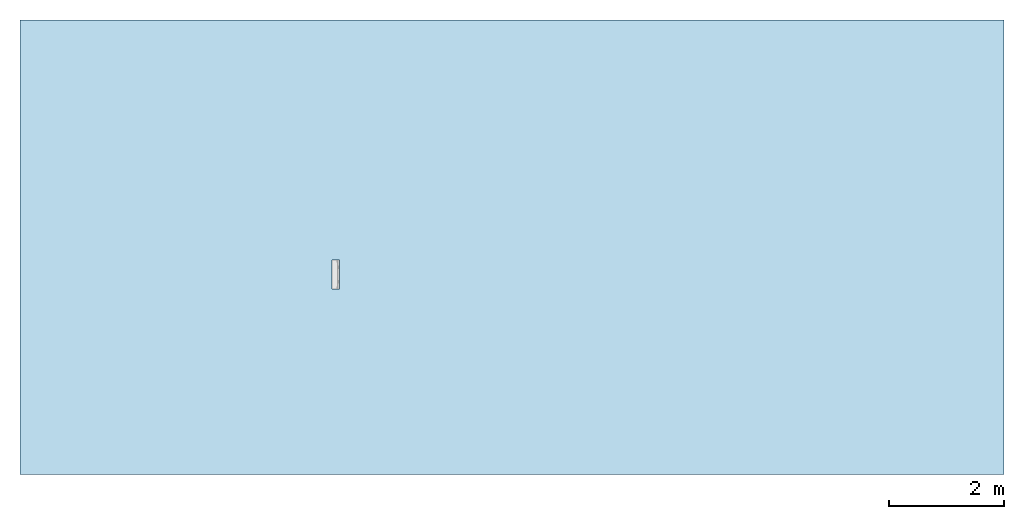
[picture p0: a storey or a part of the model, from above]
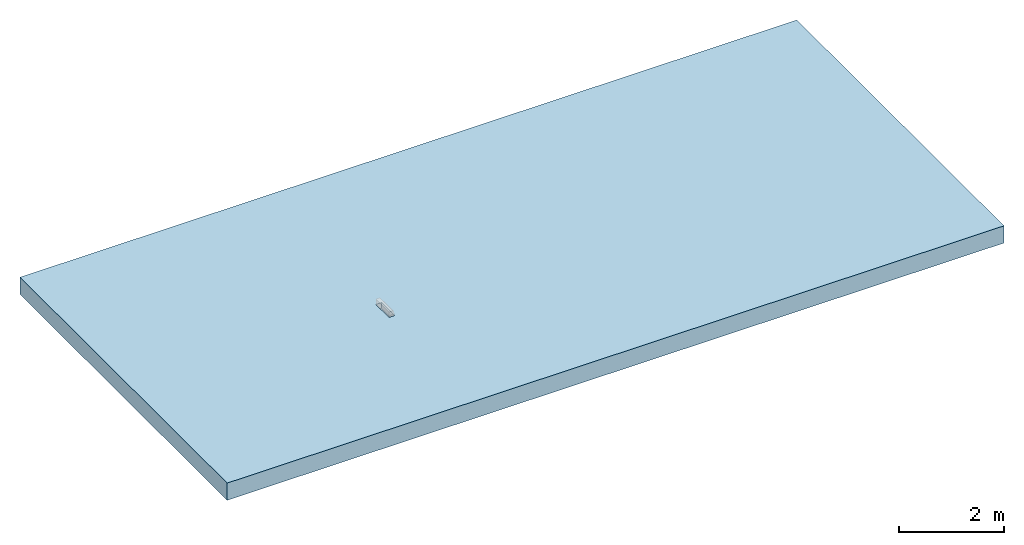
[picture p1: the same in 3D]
Properties of the parts of a building model (IFC2X3)

# File
Description: ViewDefinition [CoordinationView]
File name: 7958 - KDHB255 channel - 500mm LG.ifc
Time: 2013-08-30T17:44:03
Written by: Autodesk Revit 2013
Made in: 20120221_2030(x64)

# IfcProject, Project Number
LongName: Project Name; Phase: Project Status

# IfcSite, Default
RefLatitude: 42, 21, 30, 344238; RefLongitude: -71, -3, -35, -194702; RefElevation: 0 mm

# IfcBuilding
Pset_BuildingCommon - NumberOfStoreys: 1
Other - Project Number: Project Number; Project Issue Date: Issue Date; Client Name: Owner; Project Name: Project Name; Project Status: Project Status; Project Address: ## Street City, State Zip

# IfcBuildingStorey, Level 1
LongName: Level 1; Elevation: 0 mm
Graphics - Line Pattern: Center; Symbol at End 2 Default: yes; Symbol at End 1 Default: no; Line Weight: 1; Symbol: M_Level Head - Circle: M_Level Head - Circle; Color: 0
Constraints - Elevation Base: 0; Elevation: 0 mm
Identity Data - Structural: no; Building Story: yes; Name: Level 1
Dimensions - Computation Height: 0 mm

# IfcBuildingElementProxy: 7958 - KDHB255 channel - 500mm LG, Civil-Drainage-Channel-ACO-KerbDrain-HB255:7958 - KDHB255 channel - 500mm LG:7958 - KDHB255 channel - 500mm LG:754467
In: Level 1
Material: ACO Polymer Concrete.
Phasing - Phase Created: New Construction
Constraints - Level: Level: Level 1; Moves With Nearby Elements: no
Dimensions - Volume: 9455625 mm3; LH Void Start: -2000 mm; LH Void End: -2005 mm; Void Width: 125 mm; Void Depth: -130 mm; RH Hole End: -2005 mm; Void Length: 500 mm; Access Depth: 2000 mm; RH Void Start: -2000 mm; Void Start: 0 mm
Pset_BuildingElementProxyCommon - Reference: 7958 - KDHB255 channel - 500mm LG
General - SerialNumber: 0.000000; TagNumber: 0.000000
Identity Data - Maintenance guidelines: http://www.aco.co.uk/download.php?id=120; Fax: +44 (0)1462 815895; URL: www.aco.co.uk; Product Page URL: http://www.aco.co.uk/product_detail.php?id=3; e-mail Sales: customersupport@aco.co.uk; Type Comments: ACO KerbDrain HB255 half battered kerb unit 500mm long; Model: ACO KerbDrain HB255; Installation guidelines: http://www.aco.co.uk/download.php?id=120; Price: POA - contact ACO; Manufacturer: ACO Technologies plc - ACO Water Management Division; Cost: 0; Telephone: +44 (0)1462 816666; Product Code: 7958; Product brochure: http://www.aco.co.uk/download.php?id=120; Assembly Code: D2040; Assembly Description: Rain Water Drainage; OmniClass Title: Rainwater Removal; Model Description: Combined kerb and drainage system; Address: ACO Business Park, Hitchin Road, Shefford, Bedfordshire, United Kingdom SG17 5TE; OmniClass Number: 23.70.50.24; e-mail Technical: technical@aco.co.uk
Data - ACO Hydraulic Design Software: http://www.acodesign.co.uk; Concrete Surround Volume - Load Class A 15 - D 400 - Concrete Pavement: 0.12m³/m; Connection Pipe O.D: N/A; Product Dimensions: 500mm x 125mm x 255mm (LxWxH); Installation - Concrete Grade: Refer to brochure; Invert Depth: 235mm; Drainage Slot Intake area: 14592mm²/m; Hydraulic Performance: http://www.aco.co.uk/download.php?id=120; Channel C.S.A: 0.01m²; Concrete Surround Volume - Load Class A 15 - D 400 - Grass or Asphalt Pavement: 0.11m³/m; Product Standard: BS EN 1433:2002, CE marked, Kitemarked; Product Weight: 18.5 Kg; Drainage Slot Width: 50mm; Load Class: A 15 - D 400 A 15 - D 400
Green Building Properties - Access Cover/Frame Recycled Material Content: N/A; End Cap Recycled Material Content: N/A; Access Cover/Frame Recyclable: N/A; Channel Recyclable: Fully recyclable; Channel Recycled Material Content: 20% minimum; End Cap Recyclable: N/A
Construction - RH drop kerb: no; Closing end cap: no; LH drop kerb: no; Centre Stone: no; HB255 - 500: yes; Access Unit: no; HB255 - 1000: no
Materials and Finishes - Access Cover/Frame Finish: N/A; End Cap Material: N/A; End Cap Colour: N/A; Access Cover/Frame Colour: N/A; Channel Material: Vienite® Synthetic Resin Concrete; Channel Colour: Grey; Access Cover/Frame Material: N/A
Other - Revision: 1; CreatedBy: www.aco.co.uk

# IfcOpeningElement: Recess (3)
In: Level 1
Constraints - Room Bounding: yes; Height Offset From Level: 0 mm; Level: Level: Level 1; Related to Mass: no
Structural - Structural: no; Enable Analytical Model: no
Dimensions - Volume: 54027875000 mm3; Thickness: 400 mm; Perimeter: 50000 mm; Area: 135090000 mm2
Phasing - Phase Created: New Construction
Materials and Finishes - Structural Material: Plant
Construction - Function: 0; Default Thickness: 400 mm
Graphics - Coarse Scale Fill Color: 0
Analytical Properties - Absorptance: 0.1; Roughness: 1

# IfcSlab: Floor:Generic Floor - 400mm, Floor:Generic Floor - 400mm:193825
In: Level 1
PredefinedType: FLOOR; Material: Plant 400 mm
Constraints - Room Bounding: yes; Height Offset From Level: 0 mm; Level: Level: Level 1; Related to Mass: no
Structural - Structural: no; Enable Analytical Model: no
Dimensions - Volume: 54027875000 mm3; Thickness: 400 mm; Perimeter: 50000 mm; Area: 135090000 mm2
Phasing - Phase Created: New Construction
Pset_SlabCommon - Reference: Generic Floor - 400mm; IsExternal: no; LoadBearing: yes
Materials and Finishes - Structural Material: Plant
Construction - Function: 0; Default Thickness: 400 mm
Graphics - Coarse Scale Fill Color: 0
Analytical Properties - Absorptance: 0.1; Roughness: 1
